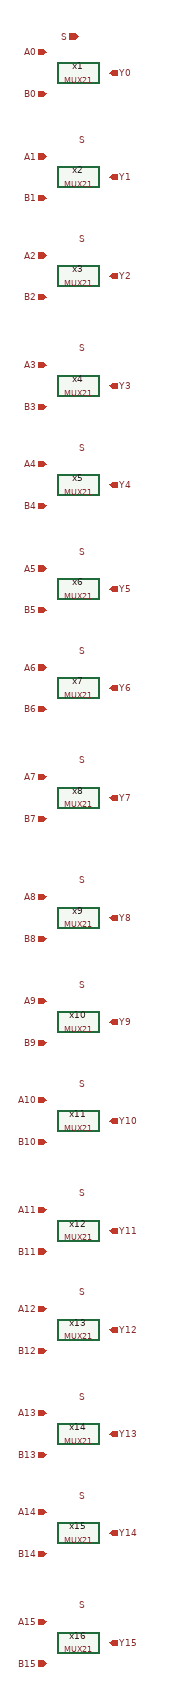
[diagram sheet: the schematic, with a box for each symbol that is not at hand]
v {xschem version=3.4.7 file_version=1.2}
G {}
K {}
V {}
S {}
E {}
C {schematics/16bit-2-1mux/MUX21.sym} 60 -40 0 0 {name=x1}
C {ipin.sym} 0 -80 0 0 {name=p3 lab=A0}
C {ipin.sym} 0 0 0 0 {name=p1 lab=B0}
C {ipin.sym} 60 -110 1 0 {name=p2 lab=S}
C {opin.sym} 120 -40 0 0 {name=p5 lab=Y0}
C {schematics/16bit-2-1mux/MUX21.sym} 60 160 0 0 {name=x2}
C {ipin.sym} 0 120 0 0 {name=p4 lab=A1}
C {ipin.sym} 0 200 0 0 {name=p6 lab=B1}
C {lab_wire.sym} 60 90 0 1 {name=p7 sig_type=std_logic lab=S}
C {opin.sym} 120 160 0 0 {name=p8 lab=Y1}
C {schematics/16bit-2-1mux/MUX21.sym} 60 350 0 0 {name=x3}
C {ipin.sym} 0 310 0 0 {name=p9 lab=A2}
C {ipin.sym} 0 390 0 0 {name=p10 lab=B2}
C {lab_wire.sym} 60 280 0 1 {name=p11 sig_type=std_logic lab=S}
C {opin.sym} 120 350 0 0 {name=p12 lab=Y2}
C {schematics/16bit-2-1mux/MUX21.sym} 60 560 0 0 {name=x4}
C {ipin.sym} 0 520 0 0 {name=p13 lab=A3}
C {ipin.sym} 0 600 0 0 {name=p14 lab=B3}
C {lab_wire.sym} 60 490 0 1 {name=p15 sig_type=std_logic lab=S}
C {opin.sym} 120 560 0 0 {name=p16 lab=Y3}
C {schematics/16bit-2-1mux/MUX21.sym} 60 750 0 0 {name=x5}
C {ipin.sym} 0 710 0 0 {name=p17 lab=A4}
C {ipin.sym} 0 790 0 0 {name=p18 lab=B4}
C {lab_wire.sym} 60 680 0 1 {name=p19 sig_type=std_logic lab=S}
C {opin.sym} 120 750 0 0 {name=p20 lab=Y4}
C {schematics/16bit-2-1mux/MUX21.sym} 60 950 0 0 {name=x6}
C {ipin.sym} 0 910 0 0 {name=p21 lab=A5}
C {ipin.sym} 0 990 0 0 {name=p22 lab=B5}
C {lab_wire.sym} 60 880 0 1 {name=p23 sig_type=std_logic lab=S}
C {opin.sym} 120 950 0 0 {name=p24 lab=Y5}
C {schematics/16bit-2-1mux/MUX21.sym} 60 1140 0 0 {name=x7}
C {ipin.sym} 0 1100 0 0 {name=p25 lab=A6}
C {ipin.sym} 0 1180 0 0 {name=p26 lab=B6}
C {lab_wire.sym} 60 1070 0 1 {name=p27 sig_type=std_logic lab=S}
C {opin.sym} 120 1140 0 0 {name=p28 lab=Y6}
C {schematics/16bit-2-1mux/MUX21.sym} 60 1350 0 0 {name=x8}
C {ipin.sym} 0 1310 0 0 {name=p29 lab=A7}
C {ipin.sym} 0 1390 0 0 {name=p30 lab=B7}
C {lab_wire.sym} 60 1280 0 1 {name=p31 sig_type=std_logic lab=S}
C {opin.sym} 120 1350 0 0 {name=p32 lab=Y7}
C {schematics/16bit-2-1mux/MUX21.sym} 60 1580 0 0 {name=x9}
C {ipin.sym} 0 1540 0 0 {name=p33 lab=A8}
C {ipin.sym} 0 1620 0 0 {name=p34 lab=B8}
C {lab_wire.sym} 60 1510 0 1 {name=p35 sig_type=std_logic lab=S}
C {opin.sym} 120 1580 0 0 {name=p36 lab=Y8}
C {schematics/16bit-2-1mux/MUX21.sym} 60 1780 0 0 {name=x10}
C {ipin.sym} 0 1740 0 0 {name=p37 lab=A9}
C {ipin.sym} 0 1820 0 0 {name=p38 lab=B9}
C {lab_wire.sym} 60 1710 0 1 {name=p39 sig_type=std_logic lab=S}
C {opin.sym} 120 1780 0 0 {name=p40 lab=Y9}
C {schematics/16bit-2-1mux/MUX21.sym} 60 1970 0 0 {name=x11}
C {ipin.sym} 0 1930 0 0 {name=p41 lab=A10}
C {ipin.sym} 0 2010 0 0 {name=p42 lab=B10}
C {lab_wire.sym} 60 1900 0 1 {name=p43 sig_type=std_logic lab=S}
C {opin.sym} 120 1970 0 0 {name=p44 lab=Y10}
C {schematics/16bit-2-1mux/MUX21.sym} 60 2180 0 0 {name=x12}
C {ipin.sym} 0 2140 0 0 {name=p45 lab=A11}
C {ipin.sym} 0 2220 0 0 {name=p46 lab=B11}
C {lab_wire.sym} 60 2110 0 1 {name=p47 sig_type=std_logic lab=S}
C {opin.sym} 120 2180 0 0 {name=p48 lab=Y11}
C {schematics/16bit-2-1mux/MUX21.sym} 60 2370 0 0 {name=x13}
C {ipin.sym} 0 2330 0 0 {name=p49 lab=A12}
C {ipin.sym} 0 2410 0 0 {name=p50 lab=B12}
C {lab_wire.sym} 60 2300 0 1 {name=p51 sig_type=std_logic lab=S}
C {opin.sym} 120 2370 0 0 {name=p52 lab=Y12}
C {schematics/16bit-2-1mux/MUX21.sym} 60 2570 0 0 {name=x14}
C {ipin.sym} 0 2530 0 0 {name=p53 lab=A13}
C {ipin.sym} 0 2610 0 0 {name=p54 lab=B13}
C {lab_wire.sym} 60 2500 0 1 {name=p55 sig_type=std_logic lab=S}
C {opin.sym} 120 2570 0 0 {name=p56 lab=Y13}
C {schematics/16bit-2-1mux/MUX21.sym} 60 2760 0 0 {name=x15}
C {ipin.sym} 0 2720 0 0 {name=p57 lab=A14}
C {ipin.sym} 0 2800 0 0 {name=p58 lab=B14}
C {lab_wire.sym} 60 2690 0 1 {name=p59 sig_type=std_logic lab=S}
C {opin.sym} 120 2760 0 0 {name=p60 lab=Y14}
C {schematics/16bit-2-1mux/MUX21.sym} 60 2970 0 0 {name=x16}
C {ipin.sym} 0 2930 0 0 {name=p61 lab=A15}
C {ipin.sym} 0 3010 0 0 {name=p62 lab=B15}
C {lab_wire.sym} 60 2900 0 1 {name=p63 sig_type=std_logic lab=S}
C {opin.sym} 120 2970 0 0 {name=p64 lab=Y15}
